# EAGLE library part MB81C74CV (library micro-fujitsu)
MICROCONTROLLER/MEMORY DEVICE

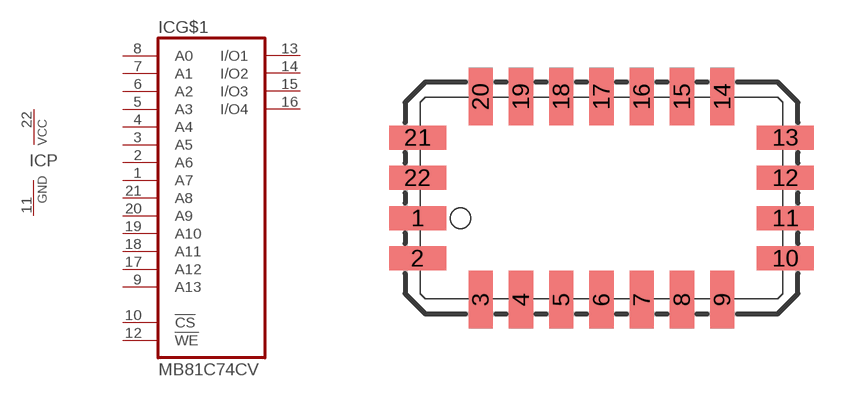
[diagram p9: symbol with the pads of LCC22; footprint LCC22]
Designator prefix IC; gates G$1=MB81C74 P=VCC-GND

## MB81C74CV (OC_FARNELL: unknown; OC_NEWARK: unknown)  [LCC22]
1  G$1:A7  in
2  G$1:A6  in
3  G$1:A5  in
4  G$1:A4  in
5  G$1:A3  in
6  G$1:A2  in
7  G$1:A1  in
8  G$1:A0  in
9  G$1:A13  in
10  G$1:!CS  in
11  P:GND  pwr
12  G$1:!WE  in
13  G$1:I/O1
14  G$1:I/O2
15  G$1:I/O3
16  G$1:I/O4
17  G$1:A12  in
18  G$1:A11  in
19  G$1:A10  in
20  G$1:A9  in
21  G$1:A8  in
22  P:VCC  pwr

## Footprint LCC22 (pad centres in mm)
LEADED CHIP CARRIER rectangle
smd 1.8 x 0.76: 1 -5.8,-0.635; 2 -5.8,-1.905; 10 5.8,-1.905; 11 5.8,-0.635; 12 5.8,0.635; 13 5.8,1.905; 21 -5.8,1.905; 22 -5.8,0.635
smd 0.76 x 1.8: 3 -3.81,-3.2; 4 -2.54,-3.2; 5 -1.27,-3.2; 6 0,-3.2; 7 1.27,-3.2; 8 2.54,-3.2; 9 3.81,-3.2; 14 3.81,3.2; 15 2.54,3.2; 16 1.27,3.2; 17 0,3.2; 18 -1.27,3.2; 19 -2.54,3.2; 20 -3.81,3.2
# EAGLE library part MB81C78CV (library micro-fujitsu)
MICROCONTROLLER/MEMORY DEVICE

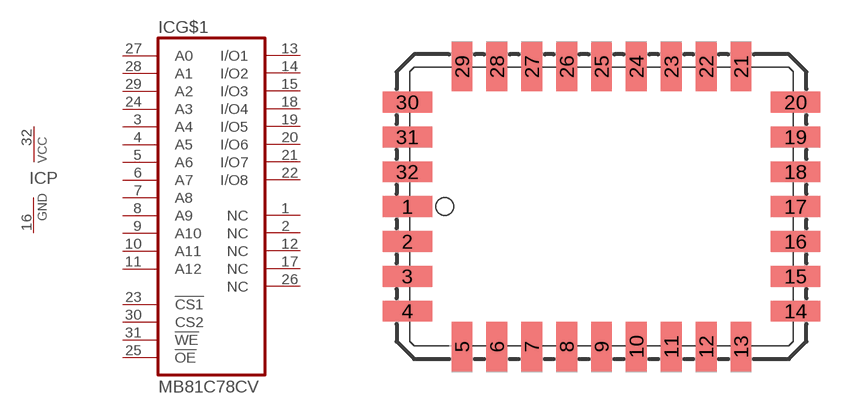
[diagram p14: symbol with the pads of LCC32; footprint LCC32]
Designator prefix IC; gates G$1=MB81C78C P=VCC-GND

## MB81C78CV (OC_FARNELL: unknown; OC_NEWARK: unknown)  [LCC32]
1  G$1:NC  nc
2  G$1:NC  nc
3  G$1:A4  in
4  G$1:A5  in
5  G$1:A6  in
6  G$1:A7  in
7  G$1:A8  in
8  G$1:A9  in
9  G$1:A10  in
10  G$1:A11  in
11  G$1:A12  in
12  G$1:NC  nc
13  G$1:I/O1
14  G$1:I/O2
15  G$1:I/O3
16  P:GND  pwr
17  G$1:NC  nc
18  G$1:I/O4  nc
19  G$1:I/O5
20  G$1:I/O6
21  G$1:I/O7
22  G$1:I/O8
23  G$1:!CS1  in
24  G$1:A3  in
25  G$1:!OE  in
26  G$1:NC  nc
27  G$1:A0  in
28  G$1:A1  in
29  G$1:A2  in
30  G$1:CS2  in
31  G$1:!WE  in
32  P:VCC  pwr

## Footprint LCC32 (pad centres in mm)
LEADED CHIP CARRIER rectangle
smd 1.8 x 0.76: 1 -7.07,0.635; 2 -7.07,-0.635; 3 -7.07,-1.905; 4 -7.07,-3.175; 14 7.07,-3.175; 15 7.07,-1.905; 16 7.07,-0.635; 17 7.07,0.635; 18 7.07,1.905; 19 7.07,3.175; 20 7.07,4.445; 30 -7.07,4.445; 31 -7.07,3.175; 32 -7.07,1.905
smd 0.76 x 1.8: 5 -5.08,-4.47; 6 -3.81,-4.47; 7 -2.54,-4.47; 8 -1.27,-4.47; 9 0,-4.47; 10 1.27,-4.47; 11 2.54,-4.47; 12 3.81,-4.47; 13 5.08,-4.47; 21 5.08,5.74; 22 3.81,5.74; 23 2.54,5.74; 24 1.27,5.74; 25 0,5.74; 26 -1.27,5.74; 27 -2.54,5.74; 28 -3.81,5.74; 29 -5.08,5.74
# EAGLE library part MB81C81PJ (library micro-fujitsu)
MICROCONTROLLER/MEMORY DEVICE

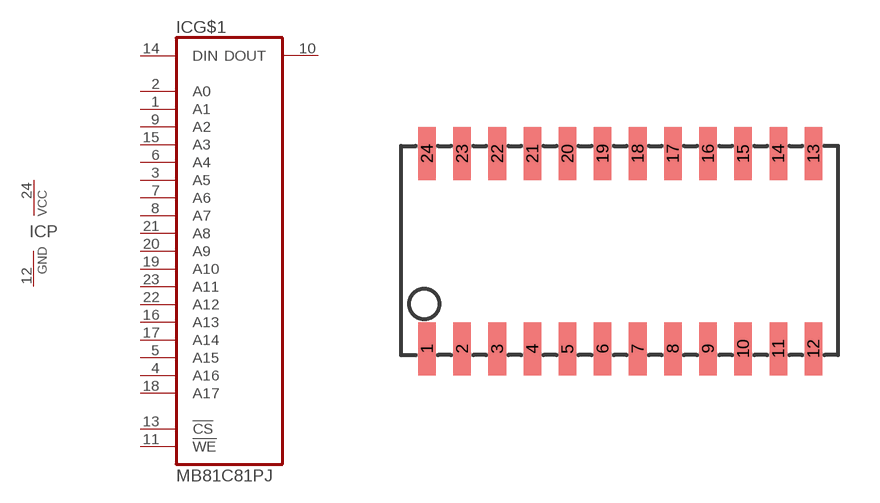
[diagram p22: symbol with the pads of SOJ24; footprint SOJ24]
Designator prefix IC; gates G$1=MB81C81 P=VCC-GND

## MB81C81PJ (OC_FARNELL: unknown; OC_NEWARK: unknown)  [SOJ24]
1  G$1:A1  in
2  G$1:A0  in
3  G$1:A5  in
4  G$1:A16  in
5  G$1:A15  in
6  G$1:A4  in
7  G$1:A6  in
8  G$1:A7  in
9  G$1:A2  in
10  G$1:DOUT  out
11  G$1:!WE  in
12  P:GND  pwr
13  G$1:!CS  in
14  G$1:DIN  in
15  G$1:A3  in
16  G$1:A13  in
17  G$1:A14  in
18  G$1:A17  in
19  G$1:A10  in
20  G$1:A9  in
21  G$1:A8  in
22  G$1:A12  in
23  G$1:A11  in
24  P:VCC  pwr

## Footprint SOJ24 (pad centres in mm)
Small Outline J-Bend
smd 0.635 x 1.905: 1 -6.985,-3.531; 2 -5.715,-3.531; 3 -4.445,-3.531; 4 -3.175,-3.531; 5 -1.905,-3.531; 6 -0.635,-3.531; 7 0.635,-3.531; 8 1.905,-3.531; 9 3.175,-3.531; 10 4.445,-3.531; 11 5.715,-3.531; 12 6.985,-3.531; 13 6.985,3.531; 14 5.715,3.531; 15 4.445,3.531; 16 3.175,3.531; 17 1.905,3.531; 18 0.635,3.531; 19 -0.635,3.531; 20 -1.905,3.531; 21 -3.175,3.531; 22 -4.445,3.531; 23 -5.715,3.531; 24 -6.985,3.531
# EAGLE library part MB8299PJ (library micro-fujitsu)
MICROCONTROLLER/MEMORY DEVICE

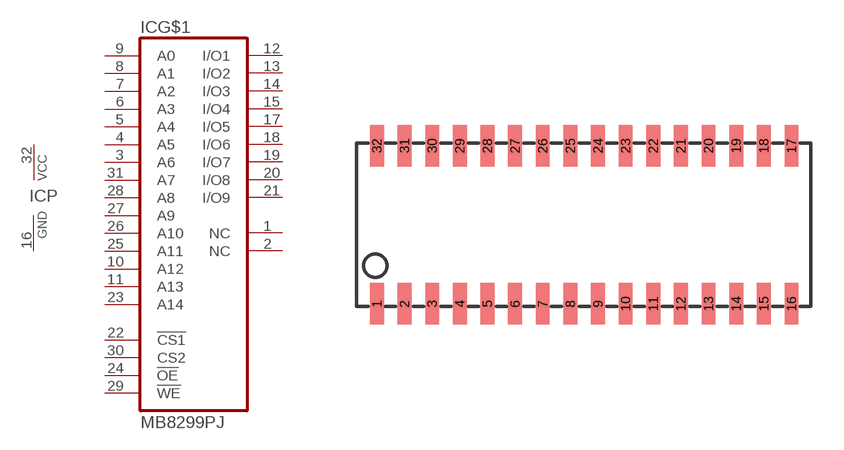
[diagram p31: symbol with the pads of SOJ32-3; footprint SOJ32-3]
Designator prefix IC; gates G$1=MB8299 P=VCC-GND

## MB8299PJ (OC_FARNELL: unknown; OC_NEWARK: unknown)  [SOJ32-3]
1  G$1:NC  nc
2  G$1:NC  nc
3  G$1:A6  in
4  G$1:A5  in
5  G$1:A4  in
6  G$1:A3  in
7  G$1:A2  in
8  G$1:A1  in
9  G$1:A0  in
10  G$1:A12  in
11  G$1:A13  in
12  G$1:I/O1
13  G$1:I/O2
14  G$1:I/O3
15  G$1:I/O4  nc
16  P:GND  pwr
17  G$1:I/O5
18  G$1:I/O6
19  G$1:I/O7
20  G$1:I/O8
21  G$1:I/O9
22  G$1:!CS1  in
23  G$1:A14  in
24  G$1:!OE  in
25  G$1:A11  in
26  G$1:A10  in
27  G$1:A9  in
28  G$1:A8  in
29  G$1:!WE  in
30  G$1:CS2  in
31  G$1:A7  in
32  P:VCC  pwr

## Footprint SOJ32-3 (pad centres in mm)
Small Outline J-Bend
smd 0.635 x 1.905: 1 -9.525,-3.632; 2 -8.255,-3.632; 3 -6.985,-3.632; 4 -5.715,-3.632; 5 -4.445,-3.632; 6 -3.175,-3.632; 7 -1.905,-3.632; 8 -0.635,-3.632; 9 0.635,-3.632; 10 1.905,-3.632; 11 3.175,-3.632; 12 4.445,-3.632; 13 5.715,-3.632; 14 6.985,-3.632; 15 8.255,-3.632; 16 9.525,-3.632; 17 9.525,3.632; 18 8.255,3.632; 19 6.985,3.632; 20 5.715,3.632; 21 4.445,3.632; 22 3.175,3.632; 23 1.905,3.632; 24 0.635,3.632; 25 -0.635,3.632; 26 -1.905,3.632; 27 -3.175,3.632; 28 -4.445,3.632; 29 -5.715,3.632; 30 -6.985,3.632; 31 -8.255,3.632; 32 -9.525,3.632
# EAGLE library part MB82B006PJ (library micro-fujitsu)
MICROCONTROLLER/MEMORY DEVICE

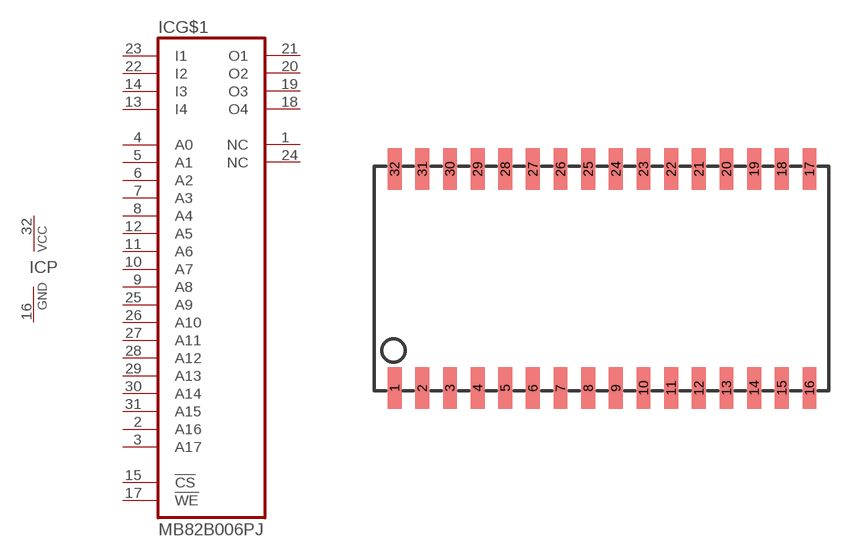
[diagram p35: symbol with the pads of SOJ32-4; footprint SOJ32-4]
Designator prefix IC; gates G$1=MB82B006 P=VCC-GND

## MB82B006PJ (OC_FARNELL: unknown; OC_NEWARK: unknown)  [SOJ32-4]
1  G$1:NC  nc
2  G$1:A16  in
3  G$1:A17  in
4  G$1:A0  in
5  G$1:A1  in
6  G$1:A2  in
7  G$1:A3  in
8  G$1:A4  in
9  G$1:A8  in
10  G$1:A7  in
11  G$1:A6  in
12  G$1:A5  in
13  G$1:I4  in
14  G$1:I3  in
15  G$1:!CS  in
16  P:GND  pwr
17  G$1:!WE  in
18  G$1:O4  out
19  G$1:O3  out
20  G$1:O2  out
21  G$1:O1  out
22  G$1:I2  in
23  G$1:I1  in
24  G$1:NC  nc
25  G$1:A9  in
26  G$1:A10  in
27  G$1:A11  in
28  G$1:A12  in
29  G$1:A13  in
30  G$1:A14  in
31  G$1:A15  in
32  P:VCC  pwr

## Footprint SOJ32-4 (pad centres in mm)
Small Outline J-Bend
smd 0.635 x 1.905: 1 -9.525,-5.029; 2 -8.255,-5.029; 3 -6.985,-5.029; 4 -5.715,-5.029; 5 -4.445,-5.029; 6 -3.175,-5.029; 7 -1.905,-5.029; 8 -0.635,-5.029; 9 0.635,-5.029; 10 1.905,-5.029; 11 3.175,-5.029; 12 4.445,-5.029; 13 5.715,-5.029; 14 6.985,-5.029; 15 8.255,-5.029; 16 9.525,-5.029; 17 9.525,5.029; 18 8.255,5.029; 19 6.985,5.029; 20 5.715,5.029; 21 4.445,5.029; 22 3.175,5.029; 23 1.905,5.029; 24 0.635,5.029; 25 -0.635,5.029; 26 -1.905,5.029; 27 -3.175,5.029; 28 -4.445,5.029; 29 -5.715,5.029; 30 -6.985,5.029; 31 -8.255,5.029; 32 -9.525,5.029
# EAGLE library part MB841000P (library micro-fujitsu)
MICROCONTROLLER/MEMORY DEVICE

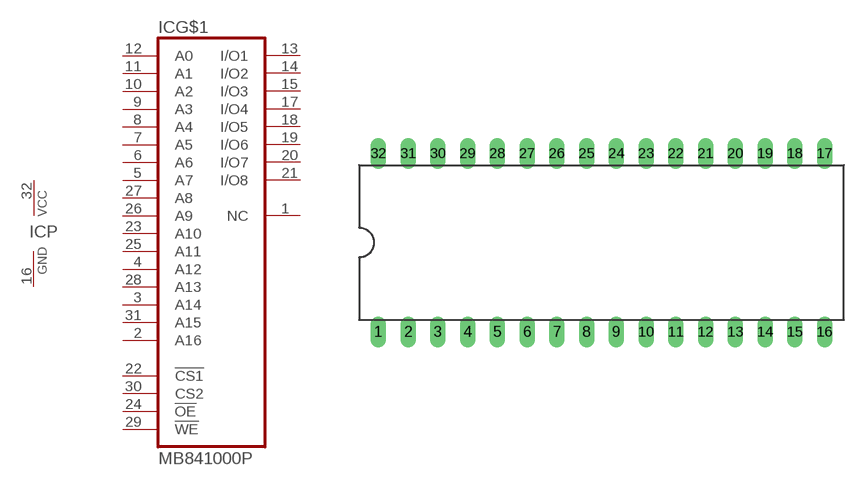
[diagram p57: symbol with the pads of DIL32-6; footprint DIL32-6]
Designator prefix IC; gates G$1=MB841000 P=VCC-GND

## MB841000P (OC_FARNELL: unknown; OC_NEWARK: unknown)  [DIL32-6]
1  G$1:NC  nc
2  G$1:A16  in
3  G$1:A14  in
4  G$1:A12  in
5  G$1:A7  in
6  G$1:A6  in
7  G$1:A5  in
8  G$1:A4  in
9  G$1:A3  in
10  G$1:A2  in
11  G$1:A1  in
12  G$1:A0  in
13  G$1:I/O1
14  G$1:I/O2
15  G$1:I/O3
16  P:GND  pwr
17  G$1:I/O4  nc
18  G$1:I/O5
19  G$1:I/O6
20  G$1:I/O7
21  G$1:I/O8
22  G$1:!CS1  in
23  G$1:A10  in
24  G$1:!OE  in
25  G$1:A11  in
26  G$1:A9  in
27  G$1:A8  in
28  G$1:A13  in
29  G$1:!WE  in
30  G$1:CS2  in
31  G$1:A15  in
32  P:VCC  pwr

## Footprint DIL32-6 (pad centres in mm)
Dual In Line
drill 0.813 long: 1 -19.05,-7.62; 2 -16.51,-7.62; 3 -13.97,-7.62; 4 -11.43,-7.62; 5 -8.89,-7.62; 6 -6.35,-7.62; 7 -3.81,-7.62; 8 -1.27,-7.62; 9 1.27,-7.62; 10 3.81,-7.62; 11 6.35,-7.62; 12 8.89,-7.62; 13 11.43,-7.62; 14 13.97,-7.62; 15 16.51,-7.62; 16 19.05,-7.62; 17 19.05,7.62; 18 16.51,7.62; 19 13.97,7.62; 20 11.43,7.62; 21 8.89,7.62; 22 6.35,7.62; 23 3.81,7.62; 24 1.27,7.62; 25 -1.27,7.62; 26 -3.81,7.62; 27 -6.35,7.62; 28 -8.89,7.62; 29 -11.43,7.62; 30 -13.97,7.62; 31 -16.51,7.62; 32 -19.05,7.62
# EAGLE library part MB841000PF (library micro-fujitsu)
MICROCONTROLLER/MEMORY DEVICE

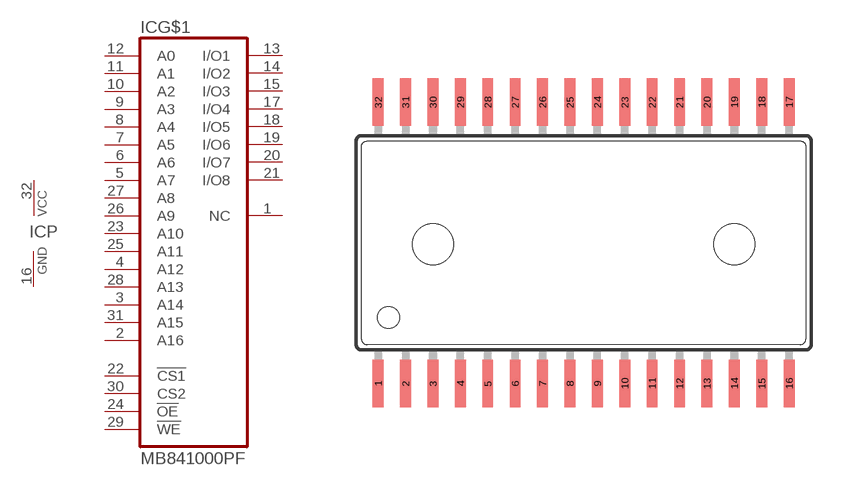
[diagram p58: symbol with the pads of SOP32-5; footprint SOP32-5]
Designator prefix IC; gates G$1=MB841000 P=VCC-GND

## MB841000PF (OC_FARNELL: unknown; OC_NEWARK: unknown)  [SOP32-5]
1  G$1:NC  nc
2  G$1:A16  in
3  G$1:A14  in
4  G$1:A12  in
5  G$1:A7  in
6  G$1:A6  in
7  G$1:A5  in
8  G$1:A4  in
9  G$1:A3  in
10  G$1:A2  in
11  G$1:A1  in
12  G$1:A0  in
13  G$1:I/O1
14  G$1:I/O2
15  G$1:I/O3
16  P:GND  pwr
17  G$1:I/O4  nc
18  G$1:I/O5
19  G$1:I/O6
20  G$1:I/O7
21  G$1:I/O8
22  G$1:!CS1  in
23  G$1:A10  in
24  G$1:!OE  in
25  G$1:A11  in
26  G$1:A9  in
27  G$1:A8  in
28  G$1:A13  in
29  G$1:!WE  in
30  G$1:CS2  in
31  G$1:A15  in
32  P:VCC  pwr

## Footprint SOP32-5 (pad centres in mm)
Small Outline Package
smd 0.5 x 2.2: 1 -9.525,-6.516; 2 -8.255,-6.516; 3 -6.985,-6.516; 4 -5.715,-6.516; 5 -4.445,-6.516; 6 -3.175,-6.516; 7 -1.905,-6.516; 8 -0.635,-6.516; 9 0.635,-6.516; 10 1.905,-6.516; 11 3.175,-6.516; 12 4.445,-6.516; 13 5.715,-6.516; 14 6.985,-6.516; 15 8.255,-6.516; 16 9.525,-6.516; 17 9.525,6.516; 18 8.255,6.516; 19 6.985,6.516; 20 5.715,6.516; 21 4.445,6.516; 22 3.175,6.516; 23 1.905,6.516; 24 0.635,6.516; 25 -0.635,6.516; 26 -1.905,6.516; 27 -3.175,6.516; 28 -4.445,6.516; 29 -5.715,6.516; 30 -6.985,6.516; 31 -8.255,6.516; 32 -9.525,6.516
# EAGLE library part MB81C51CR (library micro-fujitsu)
MICROCONTROLLER/MEMORY DEVICE

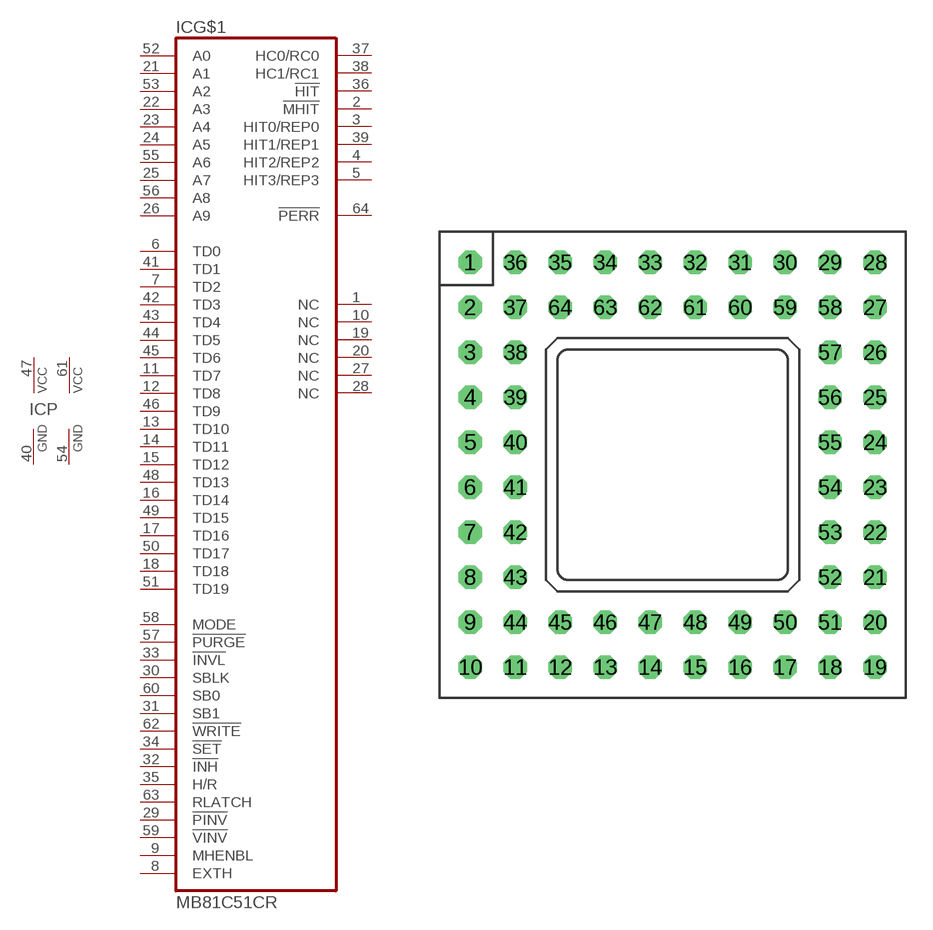
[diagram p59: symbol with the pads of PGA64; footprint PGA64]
Designator prefix IC; gates G$1=MB81C51 P=2VCC2GND

## MB81C51CR (OC_FARNELL: unknown; OC_NEWARK: unknown)  [PGA64]
1  G$1:NC  nc
2  G$1:!MHIT  out
3  G$1:HIT0/REP0  out
4  G$1:HIT2/REP2  out
5  G$1:HIT3/REP3  out
6  G$1:TD0  in
7  G$1:TD2  in
8  G$1:EXTH  in
9  G$1:MHENBL  in
10  G$1:NC  nc
11  G$1:TD7  in
12  G$1:TD8  in
13  G$1:TD10  in
14  G$1:TD11  in
15  G$1:TD12  in
16  G$1:TD14  in
17  G$1:TD16  in
18  G$1:TD18  in
19  G$1:NC  nc
20  G$1:NC  nc
21  G$1:A1  in
22  G$1:A3  in
23  G$1:A4  in
24  G$1:A5  in
25  G$1:A7  in
26  G$1:A9  in
27  G$1:NC  nc
28  G$1:NC  nc
29  G$1:!PINV  in
30  G$1:SBLK  in
31  G$1:SB1  in
32  G$1:!INH  in
33  G$1:!INVL  in
34  G$1:!SET  in
35  G$1:H/R  in
36  G$1:!HIT  out
37  G$1:HC0/RC0  out
38  G$1:HC1/RC1  out
39  G$1:HIT1/REP1  out
40  P:GND  pwr
41  G$1:TD1  in
42  G$1:TD3  in
43  G$1:TD4  in
44  G$1:TD5  in
45  G$1:TD6  in
46  G$1:TD9  in
47  P:VCC  pwr
48  G$1:TD13  in
49  G$1:TD15  in
50  G$1:TD17  in
51  G$1:TD19  in
52  G$1:A0  in
53  G$1:A2  in
54  P:GND  pwr
55  G$1:A6  in
56  G$1:A8  in
57  G$1:!PURGE  in
58  G$1:MODE  in
59  G$1:!VINV  in
60  G$1:SB0  in
61  P:VCC  pwr
62  G$1:!WRITE  in
63  G$1:RLATCH  in
64  G$1:!PERR  out

## Footprint PGA64 (pad centres in mm)
Pin Grid Array
drill 0.813 octagon: 1 -11.43,11.43; 2 -11.43,8.89; 3 -11.43,6.35; 4 -11.43,3.81; 5 -11.43,1.27; 6 -11.43,-1.27; 7 -11.43,-3.81; 8 -11.43,-6.35; 9 -11.43,-8.89; 10 -11.43,-11.43; 11 -8.89,-11.43; 12 -6.35,-11.43; 13 -3.81,-11.43; 14 -1.27,-11.43; 15 1.27,-11.43; 16 3.81,-11.43; 17 6.35,-11.43; 18 8.89,-11.43; 19 11.43,-11.43; 20 11.43,-8.89; 21 11.43,-6.35; 22 11.43,-3.81; 23 11.43,-1.27; 24 11.43,1.27; 25 11.43,3.81; 26 11.43,6.35; 27 11.43,8.89; 28 11.43,11.43; 29 8.89,11.43; 30 6.35,11.43; 31 3.81,11.43; 32 1.27,11.43; 33 -1.27,11.43; 34 -3.81,11.43; 35 -6.35,11.43; 36 -8.89,11.43; 37 -8.89,8.89; 38 -8.89,6.35; 39 -8.89,3.81; 40 -8.89,1.27; 41 -8.89,-1.27; 42 -8.89,-3.81; 43 -8.89,-6.35; 44 -8.89,-8.89; 45 -6.35,-8.89; 46 -3.81,-8.89; 47 -1.27,-8.89; 48 1.27,-8.89; 49 3.81,-8.89; 50 6.35,-8.89; 51 8.89,-8.89; 52 8.89,-6.35; 53 8.89,-3.81; 54 8.89,-1.27; 55 8.89,1.27; 56 8.89,3.81; 57 8.89,6.35; 58 8.89,8.89; 59 6.35,8.89; 60 3.81,8.89; 61 1.27,8.89; 62 -1.27,8.89; 63 -3.81,8.89; 64 -6.35,8.89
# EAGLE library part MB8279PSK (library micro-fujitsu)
MICROCONTROLLER/MEMORY DEVICE

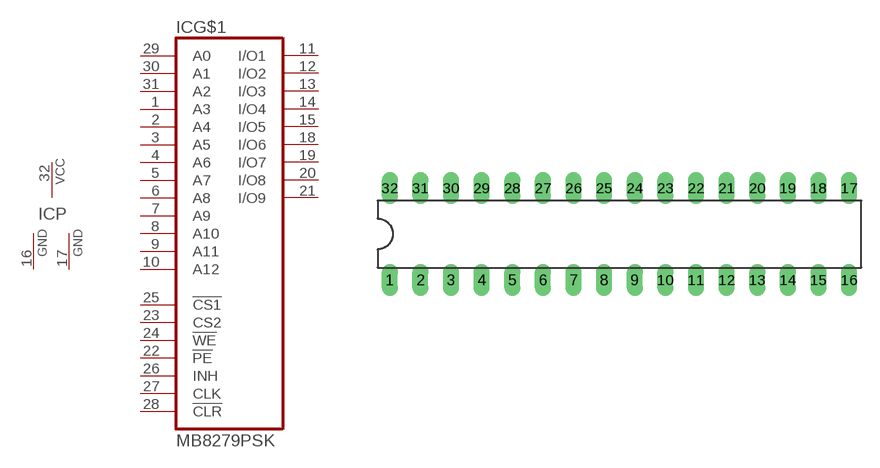
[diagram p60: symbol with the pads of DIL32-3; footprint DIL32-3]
Designator prefix IC; gates G$1=MB8279RT P=VCC-GNDQ

## MB8279PSK (OC_FARNELL: unknown; OC_NEWARK: unknown)  [DIL32-3]
1  G$1:A3  in
2  G$1:A4  in
3  G$1:A5  in
4  G$1:A6  in
5  G$1:A7  in
6  G$1:A8  in
7  G$1:A9  in
8  G$1:A10  in
9  G$1:A11  in
10  G$1:A12  in
11  G$1:I/O1
12  G$1:I/O2
13  G$1:I/O3
14  G$1:I/O4  nc
15  G$1:I/O5
16  P:GND  pwr
17  P:GNDQ  pwr
18  G$1:I/O6
19  G$1:I/O7
20  G$1:I/O8
21  G$1:I/O9
22  G$1:!PE  in
23  G$1:CS2  in
24  G$1:!WE  in
25  G$1:!CS1  in
26  G$1:INH  in
27  G$1:CLK  in
28  G$1:!CLR  in
29  G$1:A0  in
30  G$1:A1  in
31  G$1:A2  in
32  P:VCC  pwr

## Footprint DIL32-3 (pad centres in mm)
Dual In Line
drill 0.813 long: 1 -19.05,-3.81; 2 -16.51,-3.81; 3 -13.97,-3.81; 4 -11.43,-3.81; 5 -8.89,-3.81; 6 -6.35,-3.81; 7 -3.81,-3.81; 8 -1.27,-3.81; 9 1.27,-3.81; 10 3.81,-3.81; 11 6.35,-3.81; 12 8.89,-3.81; 13 11.43,-3.81; 14 13.97,-3.81; 15 16.51,-3.81; 16 19.05,-3.81; 17 19.05,3.81; 18 16.51,3.81; 19 13.97,3.81; 20 11.43,3.81; 21 8.89,3.81; 22 6.35,3.81; 23 3.81,3.81; 24 1.27,3.81; 25 -1.27,3.81; 26 -3.81,3.81; 27 -6.35,3.81; 28 -8.89,3.81; 29 -11.43,3.81; 30 -13.97,3.81; 31 -16.51,3.81; 32 -19.05,3.81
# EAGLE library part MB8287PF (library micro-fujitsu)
MICROCONTROLLER/MEMORY DEVICE

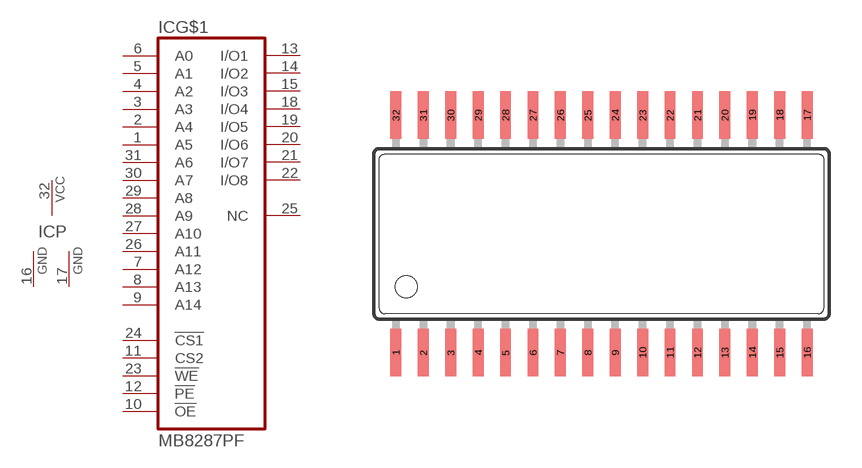
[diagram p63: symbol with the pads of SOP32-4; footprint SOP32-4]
Designator prefix IC; gates G$1=MB8287 P=VCC-GNDQ

## MB8287PF (OC_FARNELL: unknown; OC_NEWARK: unknown)  [SOP32-4]
1  G$1:A5  in
2  G$1:A4  in
3  G$1:A3  in
4  G$1:A2  in
5  G$1:A1  in
6  G$1:A0  in
7  G$1:A12  in
8  G$1:A13  in
9  G$1:A14  in
10  G$1:!OE  in
11  G$1:CS2  in
12  G$1:!PE  in
13  G$1:I/O1
14  G$1:I/O2
15  G$1:I/O3
16  P:GND  pwr
17  P:GNDQ  pwr
18  G$1:I/O4  nc
19  G$1:I/O5
20  G$1:I/O6
21  G$1:I/O7
22  G$1:I/O8
23  G$1:!WE  in
24  G$1:!CS1  in
25  G$1:NC  nc
26  G$1:A11  in
27  G$1:A10  in
28  G$1:A9  in
29  G$1:A8  in
30  G$1:A7  in
31  G$1:A6  in
32  P:VCC  pwr

## Footprint SOP32-4 (pad centres in mm)
Small Outline Package
smd 0.5 x 2.2: 1 -9.525,-5.5; 2 -8.255,-5.5; 3 -6.985,-5.5; 4 -5.715,-5.5; 5 -4.445,-5.5; 6 -3.175,-5.5; 7 -1.905,-5.5; 8 -0.635,-5.5; 9 0.635,-5.5; 10 1.905,-5.5; 11 3.175,-5.5; 12 4.445,-5.5; 13 5.715,-5.5; 14 6.985,-5.5; 15 8.255,-5.5; 16 9.525,-5.5; 17 9.525,5.5; 18 8.255,5.5; 19 6.985,5.5; 20 5.715,5.5; 21 4.445,5.5; 22 3.175,5.5; 23 1.905,5.5; 24 0.635,5.5; 25 -0.635,5.5; 26 -1.905,5.5; 27 -3.175,5.5; 28 -4.445,5.5; 29 -5.715,5.5; 30 -6.985,5.5; 31 -8.255,5.5; 32 -9.525,5.5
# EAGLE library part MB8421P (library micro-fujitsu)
MICROCONTROLLER/MEMORY DEVICE

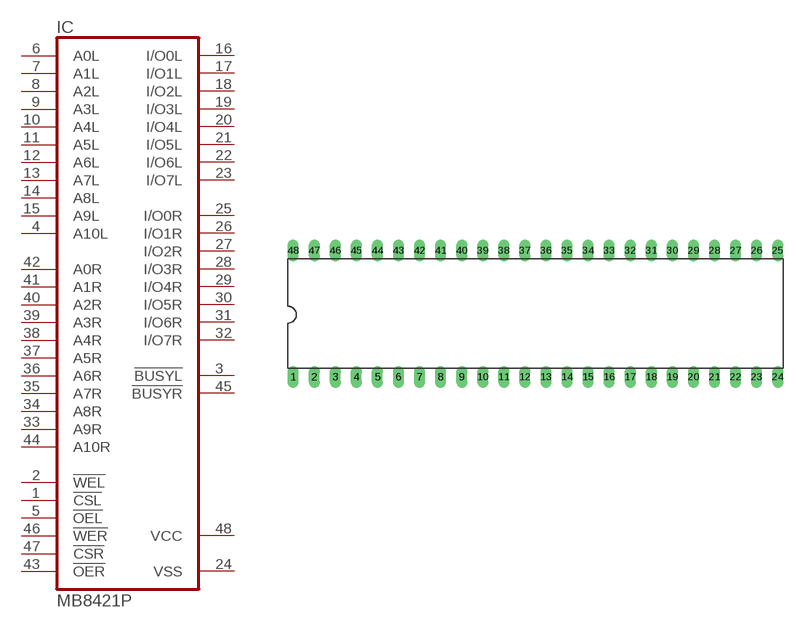
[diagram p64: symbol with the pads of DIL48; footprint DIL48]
Designator prefix IC

## MB8421P (OC_FARNELL: unknown; OC_NEWARK: unknown)  [DIL48]
1  !CSL  in
2  !WEL  in
3  !BUSYL  out
4  A10L  in
5  !OEL  in
6  A0L  in
7  A1L  in
8  A2L  in
9  A3L  in
10  A4L  in
11  A5L  in
12  A6L  in
13  A7L  in
14  A8L  in
15  A9L  in
16  I/O0L
17  I/O1L
18  I/O2L
19  I/O3L
20  I/O4L
21  I/O5L
22  I/O6L
23  I/O7L
24  VSS  pwr
25  I/O0R
26  I/O1R
27  I/O2R
28  I/O3R
29  I/O4R
30  I/O5R
31  I/O6R
32  I/O7R
33  A9R  in
34  A8R  in
35  A7R  in
36  A6R  in
37  A5R  in
38  A4R  in
39  A3R  in
40  A2R  in
41  A1R  in
42  A0R  in
43  !OER  in
44  A10R  in
45  !BUSYR  out
46  !WER  in
47  !CSR  in
48  VCC  pwr

## Footprint DIL48 (pad centres in mm)
Dual In Line Package
drill 0.813 long: 1 -29.21,-7.62; 2 -26.67,-7.62; 3 -24.13,-7.62; 4 -21.59,-7.62; 5 -19.05,-7.62; 6 -16.51,-7.62; 7 -13.97,-7.62; 8 -11.43,-7.62; 9 -8.89,-7.62; 10 -6.35,-7.62; 11 -3.81,-7.62; 12 -1.27,-7.62; 13 1.27,-7.62; 14 3.81,-7.62; 15 6.35,-7.62; 16 8.89,-7.62; 17 11.43,-7.62; 18 13.97,-7.62; 19 16.51,-7.62; 20 19.05,-7.62; 21 21.59,-7.62; 22 24.13,-7.62; 23 26.67,-7.62; 24 29.21,-7.62; 25 29.21,7.62; 26 26.67,7.62; 27 24.13,7.62; 28 21.59,7.62; 29 19.05,7.62; 30 16.51,7.62; 31 13.97,7.62; 32 11.43,7.62; 33 8.89,7.62; 34 6.35,7.62; 35 3.81,7.62; 36 1.27,7.62; 37 -1.27,7.62; 38 -3.81,7.62; 39 -6.35,7.62; 40 -8.89,7.62; 41 -11.43,7.62; 42 -13.97,7.62; 43 -16.51,7.62; 44 -19.05,7.62; 45 -21.59,7.62; 46 -24.13,7.62; 47 -26.67,7.62; 48 -29.21,7.62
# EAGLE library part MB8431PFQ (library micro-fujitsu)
MICROCONTROLLER/MEMORY DEVICE

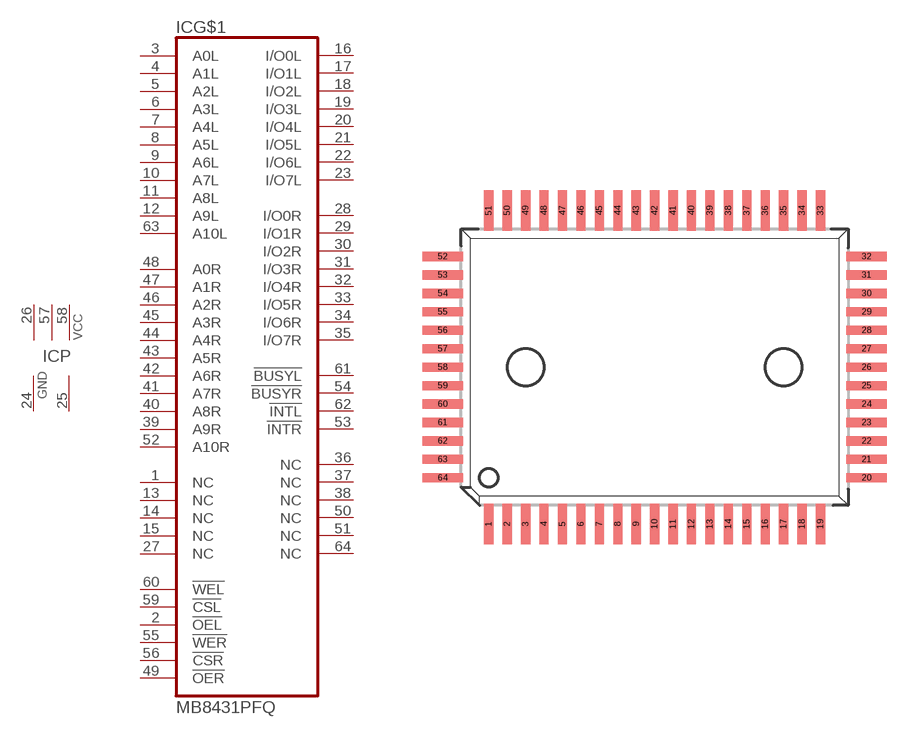
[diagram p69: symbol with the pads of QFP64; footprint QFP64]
Designator prefix IC; gates G$1=MB8431Q P=3VCC2GND

## MB8431PFQ (OC_FARNELL: unknown; OC_NEWARK: unknown)  [QFP64]
1  G$1:NC  nc
2  G$1:!OEL  in
3  G$1:A0L  in
4  G$1:A1L  in
5  G$1:A2L  in
6  G$1:A3L  in
7  G$1:A4L  in
8  G$1:A5L  in
9  G$1:A6L  in
10  G$1:A7L  in
11  G$1:A8L  in
12  G$1:A9L  in
13  G$1:NC  nc
14  G$1:NC  nc
15  G$1:NC  nc
16  G$1:I/O0L
17  G$1:I/O1L
18  G$1:I/O2L
19  G$1:I/O3L
20  G$1:I/O4L
21  G$1:I/O5L
22  G$1:I/O6L
23  G$1:I/O7L
24  P:GND  pwr
25  P:GND  pwr
26  P:VCC  pwr
27  G$1:NC  nc
28  G$1:I/O0R
29  G$1:I/O1R
30  G$1:I/O2R
31  G$1:I/O3R
32  G$1:I/O4R
33  G$1:I/O5R
34  G$1:I/O6R
35  G$1:I/O7R
36  G$1:NC  nc
37  G$1:NC  nc
38  G$1:NC  nc
39  G$1:A9R  in
40  G$1:A8R  in
41  G$1:A7R  in
42  G$1:A6R  in
43  G$1:A5R  in
44  G$1:A4R  in
45  G$1:A3R  in
46  G$1:A2R  in
47  G$1:A1R  in
48  G$1:A0R  in
49  G$1:!OER  in
50  G$1:NC  nc
51  G$1:NC  nc
52  G$1:A10R  in
53  G$1:!INTR  out
54  G$1:!BUSYR  out
55  G$1:!WER  in
56  G$1:!CSR  in
57  P:VCC  pwr
58  P:VCC  pwr
59  G$1:!CSL  in
60  G$1:!WEL  in
61  G$1:!BUSYL  out
62  G$1:!INTL  out
63  G$1:A10L  in
64  G$1:NC  nc

## Footprint QFP64 (pad centres in mm)
Quad Flat Pack
smd 0.5 x 2.2: 1 -9,-8.5; 2 -8,-8.5; 3 -7,-8.5; 4 -6,-8.5; 5 -5,-8.5; 6 -4,-8.5; 7 -3,-8.5; 8 -2,-8.5; 9 -1,-8.5; 10 0,-8.5; 11 1,-8.5; 12 2,-8.5; 13 3,-8.5; 14 4,-8.5; 15 5,-8.5; 16 6,-8.5; 17 7,-8.5; 18 8,-8.5; 19 9,-8.5; 33 9,8.5; 34 8,8.5; 35 7,8.5; 36 6,8.5; 37 5,8.5; 38 4,8.5; 39 3,8.5; 40 2,8.5; 41 1,8.5; 42 0,8.5; 43 -1,8.5; 44 -2,8.5; 45 -3,8.5; 46 -4,8.5; 47 -5,8.5; 48 -6,8.5; 49 -7,8.5; 50 -8,8.5; 51 -9,8.5
smd 2.2 x 0.5: 20 11.5,-6; 21 11.5,-5; 22 11.5,-4; 23 11.5,-3; 24 11.5,-2; 25 11.5,-1; 26 11.5,0; 27 11.5,1; 28 11.5,2; 29 11.5,3; 30 11.5,4; 31 11.5,5; 32 11.5,6; 52 -11.5,6; 53 -11.5,5; 54 -11.5,4; 55 -11.5,3; 56 -11.5,2; 57 -11.5,1; 58 -11.5,0; 59 -11.5,-1; 60 -11.5,-2; 61 -11.5,-3; 62 -11.5,-4; 63 -11.5,-5; 64 -11.5,-6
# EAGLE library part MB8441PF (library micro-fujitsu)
MICROCONTROLLER/MEMORY DEVICE

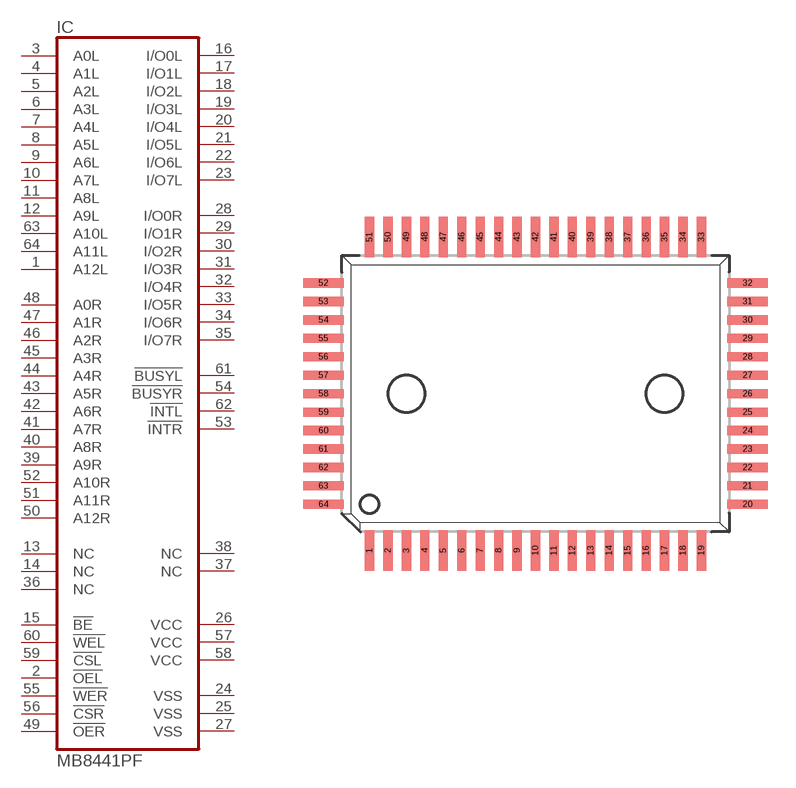
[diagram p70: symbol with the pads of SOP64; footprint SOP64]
Designator prefix IC

## MB8441PF (OC_FARNELL: unknown; OC_NEWARK: unknown)  [SOP64]
1  A12L  in
2  !OEL  in
3  A0L  in
4  A1L  in
5  A2L  in
6  A3L  in
7  A4L  in
8  A5L  in
9  A6L  in
10  A7L  in
11  A8L  in
12  A9L  in
13  NC  nc
14  NC  nc
15  !BE  in
16  I/O0L
17  I/O1L
18  I/O2L
19  I/O3L
20  I/O4L
21  I/O5L
22  I/O6L
23  I/O7L
24  VSS  pwr
25  VSS  pwr
26  VCC  pwr
27  VSS  pwr
28  I/O0R
29  I/O1R
30  I/O2R
31  I/O3R
32  I/O4R
33  I/O5R
34  I/O6R
35  I/O7R
36  NC  nc
37  NC  nc
38  NC  nc
39  A9R  in
40  A8R  in
41  A7R  in
42  A6R  in
43  A5R  in
44  A4R  in
45  A3R  in
46  A2R  in
47  A1R  in
48  A0R  in
49  !OER  in
50  A12R  in
51  A11R  in
52  A10R  in
53  !INTR  out
54  !BUSYR  out
55  !WER  in
56  !CSR  in
57  VCC  pwr
58  VCC  pwr
59  !CSL  in
60  !WEL  in
61  !BUSYL  out
62  !INTL  out
63  A10L  in
64  A11L  in

## Footprint SOP64 (pad centres in mm)
Small Outline Package rectangle
smd 0.5 x 2.2: 1 -9,-8.5; 2 -8,-8.5; 3 -7,-8.5; 4 -6,-8.5; 5 -5,-8.5; 6 -4,-8.5; 7 -3,-8.5; 8 -2,-8.5; 9 -1,-8.5; 10 0,-8.5; 11 1,-8.5; 12 2,-8.5; 13 3,-8.5; 14 4,-8.5; 15 5,-8.5; 16 6,-8.5; 17 7,-8.5; 18 8,-8.5; 19 9,-8.5; 33 9,8.5; 34 8,8.5; 35 7,8.5; 36 6,8.5; 37 5,8.5; 38 4,8.5; 39 3,8.5; 40 2,8.5; 41 1,8.5; 42 0,8.5; 43 -1,8.5; 44 -2,8.5; 45 -3,8.5; 46 -4,8.5; 47 -5,8.5; 48 -6,8.5; 49 -7,8.5; 50 -8,8.5; 51 -9,8.5
smd 2.2 x 0.5: 20 11.5,-6; 21 11.5,-5; 22 11.5,-4; 23 11.5,-3; 24 11.5,-2; 25 11.5,-1; 26 11.5,0; 27 11.5,1; 28 11.5,2; 29 11.5,3; 30 11.5,4; 31 11.5,5; 32 11.5,6; 52 -11.5,6; 53 -11.5,5; 54 -11.5,4; 55 -11.5,3; 56 -11.5,2; 57 -11.5,1; 58 -11.5,0; 59 -11.5,-1; 60 -11.5,-2; 61 -11.5,-3; 62 -11.5,-4; 63 -11.5,-5; 64 -11.5,-6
